VERSION 5.8 ;
BUSBITCHARS "[]" ;
DIVIDERCHAR "/" ;
UNITS
  DATABASE MICRONS 1000 ;
END UNITS
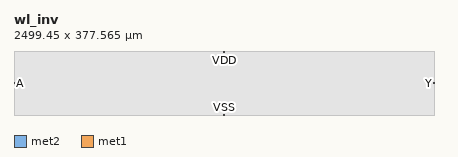
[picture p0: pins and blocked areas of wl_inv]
MACRO wl_inv
  CLASS BLOCK ;
  ORIGIN 0 0 ;
  FOREIGN wl_inv 0 0 ;
  SIZE 2499.455 BY 377.565 ;
  SYMMETRY X Y ;
  PIN A
    DIRECTION INPUT ;
    USE SIGNAL ;
    PORT
      LAYER met2 ;
        RECT 0 186.28 5 191.28 ;
    END
  END A
  PIN Y
    DIRECTION OUTPUT ;
    USE SIGNAL ;
    PORT
      LAYER met2 ;
        RECT 2494.455 186.28 2499.455 191.28 ;
    END
  END Y
  PIN VDD
    DIRECTION INOUT ;
    USE POWER ;
    PORT
      LAYER met1 ;
        RECT 1247.23 372.565 1252.23 377.565 ;
    END
  END VDD
  PIN VSS
    DIRECTION INOUT ;
    USE GROUND ;
    PORT
      LAYER met1 ;
        RECT 1247.23 0 1252.23 5 ;
    END
  END VSS
  OBS
    LAYER met1 ;
      RECT 0 0 2499.455 377.565 ;
  END
END wl_inv
END LIBRARY
